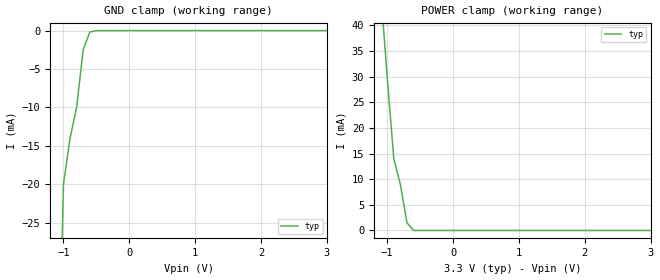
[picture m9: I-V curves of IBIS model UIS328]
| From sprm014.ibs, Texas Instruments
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[Model]   UIS328
Model_type   Input
Polarity   Non-Inverting
| signals   ALLOW, DSETPMEST, ZRINGDET, ZRINGPME, RINGINZ, ZSETSTATUS
Vinl = 0.8V
Vinh = 2.0V
|   typ   min   max
C_comp   1.7972p   1.7814p   2.0519p
|   typ   min   max
[Temperature Range]   25.0   0   90
|   typ   min   max
[Voltage Range]   3.3V   3.13V   3.47V
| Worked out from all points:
|   GND clamp passes 1 mA (typ) near -0.63 V on its own axis
|   POWER clamp passes 1 mA (typ) near -0.67 V on its own axis
[GND_clamp]
|   Voltage   I(typ)   I(min)   I(max)
-3V       -900mA     NA         NA
-2V       -400mA     NA         NA
-1V       -20mA      NA         NA
-900mV    -14mA      NA         NA
-800mV    -10mA      NA         NA
-700mV    -2.5mA     NA         NA
-600mV    -200uA     NA         NA
-500mV    0A         NA         NA
3V        0A         NA         NA
[POWER_clamp]
|   Voltage   I(typ)   I(min)   I(max)
-3V       600mA      NA         NA
-2V       200mA      NA         NA
-1V       30mA       NA         NA
-900mV    14mA       NA         NA
-800mV    9mA        NA         NA
-700mV    1.5mA      NA         NA
-600mV    0A         NA         NA
-500mV    0A         NA         NA
3V        0A         NA         NA
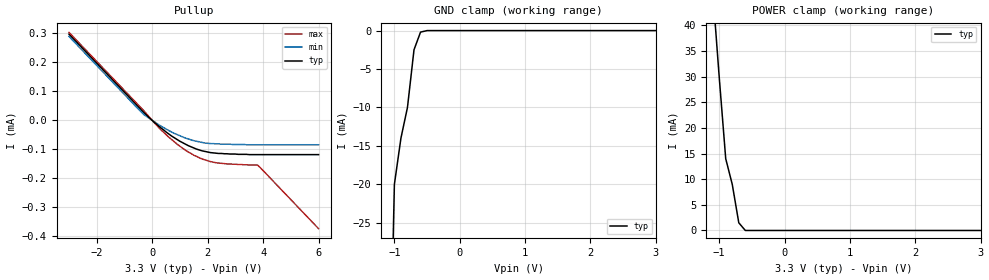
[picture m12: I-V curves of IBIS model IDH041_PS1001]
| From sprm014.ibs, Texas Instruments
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[Model]   IDH041_PS1001
Model_type   Input
Polarity   Non-Inverting
| signals   A, PWRDN, TAP, Y
Vinl = 0.8V
Vinh = 2.0V
|   typ   min   max
C_comp   3.6585p   3.6293p   4.1794p
|   typ   min   max
[Temperature Range]   25.0   0   90
|   typ   min   max
[Voltage Range]   3.3V   3.13V   3.47V
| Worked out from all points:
|   slope of the pullup table from 0 to 0.495 V, typ, clamps not added: 12.5 kohm
|   GND clamp passes 1 mA (typ) near -0.63 V on its own axis
|   POWER clamp passes 1 mA (typ) near -0.67 V on its own axis
[GND_clamp]
|   Voltage   I(typ)   I(min)   I(max)
-3V       -900mA     NA         NA
-2V       -400mA     NA         NA
-1V       -20mA      NA         NA
-900mV    -14mA      NA         NA
-800mV    -10mA      NA         NA
-700mV    -2.5mA     NA         NA
-600mV    -200uA     NA         NA
-500mV    0A         NA         NA
3V        0A         NA         NA
[Pullup]
|   Voltage   I(typ)   I(min)   I(max)
-3V       297uA      289uA      303uA
-300mV    27uA       20uA       33uA
100mV     -9uA       -6uA       -11uA
600mV     -47uA      -35uA      -58uA
1V        -72uA      -53uA      -89uA
1.3V      -87uA      -64uA      -109uA
1.8V      -105uA     -76uA      -133uA
2.3V      -113uA     -81uA      -146uA
3.8V      -118uA     -84uA      -154uA
6V        -118uA     -84uA      -373uA
[POWER_clamp]
|   Voltage   I(typ)   I(min)   I(max)
-3V       600mA      NA         NA
-2V       200mA      NA         NA
-1V       30mA       NA         NA
-900mV    14mA       NA         NA
-800mV    9mA        NA         NA
-700mV    1.5mA      NA         NA
-600mV    0A         NA         NA
-500mV    0A         NA         NA
3V        0A         NA         NA
